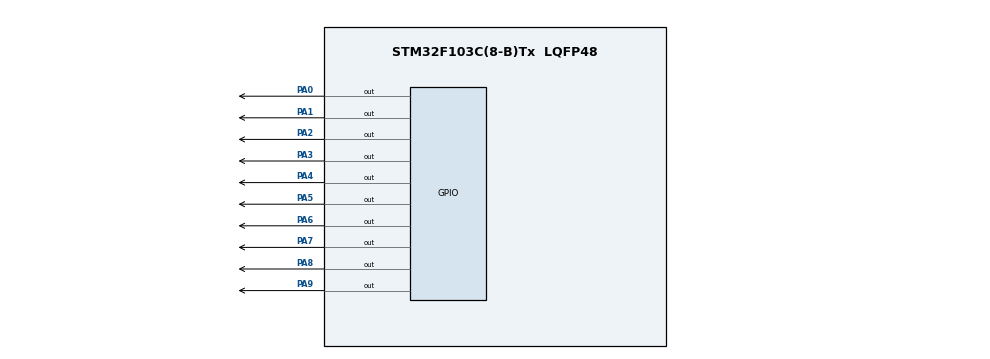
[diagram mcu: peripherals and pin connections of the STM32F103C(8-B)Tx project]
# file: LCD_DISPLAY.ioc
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Mcu.Family=STM32F1
Mcu.Name=STM32F103C(8-B)Tx
Mcu.Package=LQFP48
NVIC.PriorityGroup=NVIC_PRIORITYGROUP_4
PA0-WKUP.Signal=GPIO_Output
PA1.Signal=GPIO_Output
PA2.Signal=GPIO_Output
PA3.Signal=GPIO_Output
PA4.Signal=GPIO_Output
PA5.Signal=GPIO_Output
PA6.Signal=GPIO_Output
PA7.Signal=GPIO_Output
PA8.Signal=GPIO_Output
PA9.Signal=GPIO_Output
ProjectManager.HeapSize=0x200
ProjectManager.StackSize=0x400
ProjectManager.TargetToolchain=STM32CubeIDE
RCC.APB1Freq_Value=8000000
RCC.APB2Freq_Value=8000000
board=custom

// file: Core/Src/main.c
/* USER CODE BEGIN Header */
/**
  ******************************************************************************
  * @file           : main.c
  * @brief          : Main program body
  ******************************************************************************
  * @attention
  *
  * Copyright (c) 2024 STMicroelectronics.
  * All rights reserved.
  *
  * This software is licensed under terms that can be found in the LICENSE file
  * in the root directory of this software component.
  * If no LICENSE file comes with this software, it is provided AS-IS.
  *
  ******************************************************************************
  */
/* USER CODE END Header */
#include "main.h"

void SystemClock_Config(void);
static void MX_GPIO_Init(void);

GPIO_TypeDef  *lcdPort;
uint16_t      lcdRSPin;
uint16_t      lcdENPin;
uint16_t      lcdDataPin[8];
void lcdSetup(GPIO_TypeDef *Port, uint16_t RS, uint16_t EN, uint16_t DO, uint16_t D1,uint16_t D2,uint16_t D3,uint16_t D4,uint16_t D5,uint16_t D6,uint16_t D7 );
void lcdEnable(void);
void lcdWrite(uint8_t data);
void lcdCommand(uint8_t command);
void lcdinit();
void lcdChar(uint8_t ch);
int main(void)
{

  /* MCU Configuration--------------------------------------------------------*/

  /* Reset of all peripherals, Initializes the Flash interface and the Systick. */
  HAL_Init();

  /* Configure the system clock */
  SystemClock_Config();

  /* Initialize all configured peripherals */
  MX_GPIO_Init();

  /* Infinite loop */
  /* USER CODE BEGIN WHILE */
uint8_t a = 0;
lcdSetup(GPIOA, GPIO_PIN_8, GPIO_PIN_9, GPIO_PIN_0, GPIO_PIN_1, GPIO_PIN_2, GPIO_PIN_3, GPIO_PIN_4, GPIO_PIN_5, GPIO_PIN_6, GPIO_PIN_7);
lcdinit();
//lcdChar('E');
//lcdChar('M');
//lcdChar('C');
//lcdChar('O');
//lcdChar('G');
//lcdChar(' ');
//lcdChar('S');
//lcdChar('O');
//lcdChar('L');
//lcdChar('U');
//lcdChar('T');
//lcdChar('I');
//lcdChar('O');
//lcdChar('N');
lcdChar(a+48);
  while (1)
  {

    /* USER CODE END WHILE */

  }
}

void lcdSetup(GPIO_TypeDef *Port, uint16_t RS, uint16_t EN, uint16_t DO, uint16_t D1,uint16_t D2,uint16_t D3,uint16_t D4,uint16_t D5,uint16_t D6,uint16_t D7 ){

	lcdPort = Port;
	lcdRSPin = RS;
	lcdENPin = EN;
	lcdDataPin[0]=DO;
	lcdDataPin[1]=D1;
	lcdDataPin[2]=D2;
	lcdDataPin[3]=D3;
	lcdDataPin[4]=D4;
	lcdDataPin[5]=D5;
	lcdDataPin[6]=D6;
	lcdDataPin[7]=D7;

}
void lcdEnable(){
	HAL_GPIO_WritePin(lcdPort, lcdENPin, GPIO_PIN_SET);
	HAL_Delay(1);
	HAL_GPIO_WritePin(lcdPort, lcdENPin, GPIO_PIN_RESET);
}
void lcdWrite(uint8_t data){

	for(int i =0; i <8;i++){

		if(data & (1<<i)){
			HAL_GPIO_WritePin(lcdPort,lcdDataPin[i],GPIO_PIN_SET);
		}
		else{
			HAL_GPIO_WritePin(lcdPort,lcdDataPin[i],GPIO_PIN_RESET);
		}
	}
	lcdEnable();
}
void lcdCommand(uint8_t command){
	HAL_GPIO_WritePin(lcdPort,lcdRSPin,GPIO_PIN_RESET);
	lcdWrite(command);
}
void lcdinit(){
	lcdCommand(0X30);HAL_Delay(10);
	lcdCommand(0X30);HAL_Delay(10);
	lcdCommand(0X30);HAL_Delay(10);
	lcdCommand(0X38);HAL_Delay(10);
	lcdCommand(0X0E);HAL_Delay(10);
}
void lcdChar(uint8_t ch){
	HAL_GPIO_WritePin(lcdPort,lcdRSPin, GPIO_PIN_SET);
	lcdWrite(ch);
}
void SystemClock_Config(void)
{
  RCC_OscInitTypeDef RCC_OscInitStruct = {0};
  RCC_ClkInitTypeDef RCC_ClkInitStruct = {0};

  /** Initializes the RCC Oscillators according to the specified parameters
  * in the RCC_OscInitTypeDef structure.
  */
  RCC_OscInitStruct.OscillatorType = RCC_OSCILLATORTYPE_HSI;
  RCC_OscInitStruct.HSIState = RCC_HSI_ON;
  RCC_OscInitStruct.HSICalibrationValue = RCC_HSICALIBRATION_DEFAULT;
  RCC_OscInitStruct.PLL.PLLState = RCC_PLL_NONE;
  if (HAL_RCC_OscConfig(&RCC_OscInitStruct) != HAL_OK)
  {
    Error_Handler();
  }

  /** Initializes the CPU, AHB and APB buses clocks
  */
  RCC_ClkInitStruct.ClockType = RCC_CLOCKTYPE_HCLK|RCC_CLOCKTYPE_SYSCLK
                              |RCC_CLOCKTYPE_PCLK1|RCC_CLOCKTYPE_PCLK2;
  RCC_ClkInitStruct.SYSCLKSource = RCC_SYSCLKSOURCE_HSI;
  RCC_ClkInitStruct.AHBCLKDivider = RCC_SYSCLK_DIV1;
  RCC_ClkInitStruct.APB1CLKDivider = RCC_HCLK_DIV1;
  RCC_ClkInitStruct.APB2CLKDivider = RCC_HCLK_DIV1;

  if (HAL_RCC_ClockConfig(&RCC_ClkInitStruct, FLASH_LATENCY_0) != HAL_OK)
  {
    Error_Handler();
  }
}

static void MX_GPIO_Init(void)
{
  GPIO_InitTypeDef GPIO_InitStruct = {0};

  /* GPIO Ports Clock Enable */
  __HAL_RCC_GPIOA_CLK_ENABLE();
  __HAL_RCC_GPIOB_CLK_ENABLE();

  /*Configure GPIO pin Output Level */
  HAL_GPIO_WritePin(GPIOA, GPIO_PIN_0|GPIO_PIN_1|GPIO_PIN_2|GPIO_PIN_3
                          |GPIO_PIN_4|GPIO_PIN_5|GPIO_PIN_6|GPIO_PIN_7|GPIO_PIN_8|GPIO_PIN_9, GPIO_PIN_RESET);

  /*Configure GPIO pin Output Level */
  HAL_GPIO_WritePin(GPIOB, GPIO_PIN_0|GPIO_PIN_1, GPIO_PIN_RESET);

  /*Configure GPIO pins : PA0 PA1 PA2 PA3
                           PA4 PA5 PA6 PA7 */
  GPIO_InitStruct.Pin = GPIO_PIN_0|GPIO_PIN_1|GPIO_PIN_2|GPIO_PIN_3
                          |GPIO_PIN_4|GPIO_PIN_5|GPIO_PIN_6|GPIO_PIN_7|GPIO_PIN_8|GPIO_PIN_9;
  GPIO_InitStruct.Mode = GPIO_MODE_OUTPUT_PP;
  GPIO_InitStruct.Pull = GPIO_NOPULL;
  GPIO_InitStruct.Speed = GPIO_SPEED_FREQ_LOW;
  HAL_GPIO_Init(GPIOA, &GPIO_InitStruct);

  /*Configure GPIO pins : PB0 PB1 */
  GPIO_InitStruct.Pin = GPIO_PIN_0|GPIO_PIN_1;
  GPIO_InitStruct.Mode = GPIO_MODE_OUTPUT_PP;
  GPIO_InitStruct.Pull = GPIO_NOPULL;
  GPIO_InitStruct.Speed = GPIO_SPEED_FREQ_LOW;
  HAL_GPIO_Init(GPIOB, &GPIO_InitStruct);

}

void Error_Handler(void)
{
  __disable_irq();
  while (1)
  {
  }
}
